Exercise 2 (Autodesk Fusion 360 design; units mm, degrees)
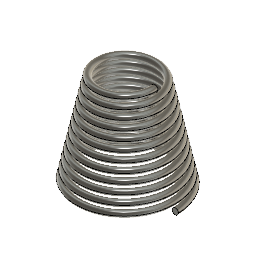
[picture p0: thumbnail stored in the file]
coil_primitive "CoilPrimitive1" Diameter 60 SectionSize 4 TaperAngle -12 Revolutions 12 Pitch 5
